VERSION 5.7 ;
  NOWIREEXTENSIONATPIN ON ;
  DIVIDERCHAR "/" ;
  BUSBITCHARS "[]" ;
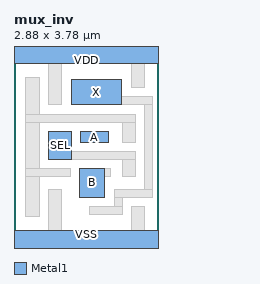
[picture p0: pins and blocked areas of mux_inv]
MACRO mux_inv
  CLASS CORE ;
  FOREIGN mux_inv ;
  ORIGIN 0.000 0.000 ;
  SIZE 2.880 BY 3.780 ;
  SITE CoreSite ;
  SYMMETRY X Y ;
  PIN X
    DIRECTION OUTPUT ;
    ANTENNADIFFAREA 0.646000 ;
    PORT
      LAYER Metal1 ;
        RECT 1.150 2.730 2.145 3.230 ;
    END
  END X
  PIN VDD
    DIRECTION INOUT ;
    USE POWER ;
    PORT
      LAYER Metal1 ;
        RECT 0.000 3.560 2.880 4.000 ;
    END
  END VDD
  PIN VSS
    DIRECTION INOUT ;
    USE GROUND ;
    PORT
      LAYER Metal1 ;
        RECT 0.000 -0.220 2.880 0.220 ;
    END
  END VSS
  PIN SEL
    DIRECTION INPUT ;
    ANTENNAGATEAREA 0.442000 ;
    PORT
      LAYER Metal1 ;
        RECT 0.690 1.640 1.150 2.190 ;
    END
  END SEL
  PIN B
    DIRECTION INPUT ;
    ANTENNAGATEAREA 0.221000 ;
    PORT
      LAYER Metal1 ;
        RECT 1.300 0.890 1.810 1.460 ;
    END
  END B
  PIN A
    DIRECTION INPUT ;
    ANTENNAGATEAREA 0.221000 ;
    PORT
      LAYER Metal1 ;
        RECT 1.330 1.980 1.880 2.190 ;
    END
  END A
  OBS
      LAYER Metal1 ;
        RECT 0.230 2.530 0.510 3.280 ;
        RECT 0.690 2.730 0.950 3.560 ;
        RECT 2.330 3.070 2.590 3.560 ;
        RECT 2.145 2.730 2.760 2.890 ;
        RECT 0.230 2.370 2.420 2.530 ;
        RECT 0.230 1.460 0.510 2.370 ;
        RECT 2.155 1.980 2.420 2.370 ;
        RECT 1.150 1.640 2.420 1.800 ;
        RECT 0.230 1.300 1.120 1.460 ;
        RECT 1.810 1.300 1.910 1.460 ;
        RECT 2.160 1.300 2.420 1.640 ;
        RECT 0.230 0.500 0.510 1.300 ;
        RECT 2.600 1.050 2.760 2.730 ;
        RECT 0.690 0.220 0.950 1.050 ;
        RECT 1.990 0.890 2.760 1.050 ;
        RECT 1.990 0.710 2.150 0.890 ;
        RECT 1.510 0.550 2.150 0.710 ;
        RECT 2.330 0.220 2.590 0.710 ;
  END
END mux_inv
END LIBRARY

